# Generated by FakeRAM 2.0
VERSION 5.7 ;
BUSBITCHARS "[]" ;
PROPERTYDEFINITIONS
  MACRO width INTEGER ;
  MACRO depth INTEGER ;
  MACRO banks INTEGER ;
END PROPERTYDEFINITIONS
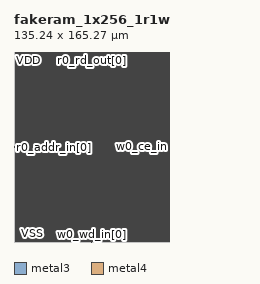
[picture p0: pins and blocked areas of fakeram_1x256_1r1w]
MACRO fakeram_1x256_1r1w
  PROPERTY width 1 ;
  PROPERTY depth 256 ;
  PROPERTY banks 1 ;
  FOREIGN fakeram_1x256_1r1w 0 0 ;
  SYMMETRY X Y R90 ;
  SIZE 135.240 BY 165.270 ;
  CLASS BLOCK ;
  PIN r0_addr_in[0]
    DIRECTION INPUT ;
    USE SIGNAL ;
    SHAPE ABUTMENT ;
    PORT
      LAYER metal3 ;
      RECT 0.000 81.900 0.070 81.970 ;
    END
  END r0_addr_in[0]
  PIN r0_addr_in[1]
    DIRECTION INPUT ;
    USE SIGNAL ;
    SHAPE ABUTMENT ;
    PORT
      LAYER metal3 ;
      RECT 0.000 82.040 0.070 82.110 ;
    END
  END r0_addr_in[1]
  PIN r0_addr_in[2]
    DIRECTION INPUT ;
    USE SIGNAL ;
    SHAPE ABUTMENT ;
    PORT
      LAYER metal3 ;
      RECT 0.000 82.180 0.070 82.250 ;
    END
  END r0_addr_in[2]
  PIN r0_addr_in[3]
    DIRECTION INPUT ;
    USE SIGNAL ;
    SHAPE ABUTMENT ;
    PORT
      LAYER metal3 ;
      RECT 0.000 82.320 0.070 82.390 ;
    END
  END r0_addr_in[3]
  PIN r0_addr_in[4]
    DIRECTION INPUT ;
    USE SIGNAL ;
    SHAPE ABUTMENT ;
    PORT
      LAYER metal3 ;
      RECT 0.000 82.460 0.070 82.530 ;
    END
  END r0_addr_in[4]
  PIN r0_addr_in[5]
    DIRECTION INPUT ;
    USE SIGNAL ;
    SHAPE ABUTMENT ;
    PORT
      LAYER metal3 ;
      RECT 0.000 82.600 0.070 82.670 ;
    END
  END r0_addr_in[5]
  PIN r0_addr_in[6]
    DIRECTION INPUT ;
    USE SIGNAL ;
    SHAPE ABUTMENT ;
    PORT
      LAYER metal3 ;
      RECT 0.000 82.740 0.070 82.810 ;
    END
  END r0_addr_in[6]
  PIN r0_addr_in[7]
    DIRECTION INPUT ;
    USE SIGNAL ;
    SHAPE ABUTMENT ;
    PORT
      LAYER metal3 ;
      RECT 0.000 82.880 0.070 82.950 ;
    END
  END r0_addr_in[7]
  PIN r0_ce_in
    DIRECTION INPUT ;
    USE SIGNAL ;
    SHAPE ABUTMENT ;
    PORT
      LAYER metal3 ;
      RECT 0.000 83.160 0.070 83.230 ;
    END
  END r0_ce_in
  PIN r0_clk
    DIRECTION INPUT ;
    USE SIGNAL ;
    SHAPE ABUTMENT ;
    PORT
      LAYER metal3 ;
      RECT 0.000 83.300 0.070 83.370 ;
    END
  END r0_clk
  PIN r0_rd_out[0]
    DIRECTION OUTPUT ;
    USE SIGNAL ;
    SHAPE ABUTMENT ;
    PORT
      LAYER metal3 ;
      RECT 67.585 165.200 67.655 165.270 ;
    END
  END r0_rd_out[0]
  PIN w0_addr_in[0]
    DIRECTION INPUT ;
    USE SIGNAL ;
    SHAPE ABUTMENT ;
    PORT
      LAYER metal3 ;
      RECT 135.170 81.900 135.240 81.970 ;
    END
  END w0_addr_in[0]
  PIN w0_addr_in[1]
    DIRECTION INPUT ;
    USE SIGNAL ;
    SHAPE ABUTMENT ;
    PORT
      LAYER metal3 ;
      RECT 135.170 82.040 135.240 82.110 ;
    END
  END w0_addr_in[1]
  PIN w0_addr_in[2]
    DIRECTION INPUT ;
    USE SIGNAL ;
    SHAPE ABUTMENT ;
    PORT
      LAYER metal3 ;
      RECT 135.170 82.180 135.240 82.250 ;
    END
  END w0_addr_in[2]
  PIN w0_addr_in[3]
    DIRECTION INPUT ;
    USE SIGNAL ;
    SHAPE ABUTMENT ;
    PORT
      LAYER metal3 ;
      RECT 135.170 82.320 135.240 82.390 ;
    END
  END w0_addr_in[3]
  PIN w0_addr_in[4]
    DIRECTION INPUT ;
    USE SIGNAL ;
    SHAPE ABUTMENT ;
    PORT
      LAYER metal3 ;
      RECT 135.170 82.460 135.240 82.530 ;
    END
  END w0_addr_in[4]
  PIN w0_addr_in[5]
    DIRECTION INPUT ;
    USE SIGNAL ;
    SHAPE ABUTMENT ;
    PORT
      LAYER metal3 ;
      RECT 135.170 82.600 135.240 82.670 ;
    END
  END w0_addr_in[5]
  PIN w0_addr_in[6]
    DIRECTION INPUT ;
    USE SIGNAL ;
    SHAPE ABUTMENT ;
    PORT
      LAYER metal3 ;
      RECT 135.170 82.740 135.240 82.810 ;
    END
  END w0_addr_in[6]
  PIN w0_addr_in[7]
    DIRECTION INPUT ;
    USE SIGNAL ;
    SHAPE ABUTMENT ;
    PORT
      LAYER metal3 ;
      RECT 135.170 82.880 135.240 82.950 ;
    END
  END w0_addr_in[7]
  PIN w0_we_in
    DIRECTION INPUT ;
    USE SIGNAL ;
    SHAPE ABUTMENT ;
    PORT
      LAYER metal3 ;
      RECT 135.170 83.160 135.240 83.230 ;
    END
  END w0_we_in
  PIN w0_ce_in
    DIRECTION INPUT ;
    USE SIGNAL ;
    SHAPE ABUTMENT ;
    PORT
      LAYER metal3 ;
      RECT 135.170 83.300 135.240 83.370 ;
    END
  END w0_ce_in
  PIN w0_clk
    DIRECTION INPUT ;
    USE SIGNAL ;
    SHAPE ABUTMENT ;
    PORT
      LAYER metal3 ;
      RECT 135.170 83.440 135.240 83.510 ;
    END
  END w0_clk
  PIN w0_wd_in[0]
    DIRECTION INPUT ;
    USE SIGNAL ;
    SHAPE ABUTMENT ;
    PORT
      LAYER metal3 ;
      RECT 67.585 0.000 67.655 0.070 ;
    END
  END w0_wd_in[0]
  PIN VSS
    DIRECTION INOUT ;
    USE GROUND ;
    PORT
      LAYER metal4 ;
      RECT 2.450 0.140 2.730 165.130 ;
      RECT 4.690 0.140 4.970 165.130 ;
      RECT 6.930 0.140 7.210 165.130 ;
      RECT 9.170 0.140 9.450 165.130 ;
      RECT 11.410 0.140 11.690 165.130 ;
      RECT 13.650 0.140 13.930 165.130 ;
      RECT 15.890 0.140 16.170 165.130 ;
      RECT 18.130 0.140 18.410 165.130 ;
      RECT 20.370 0.140 20.650 165.130 ;
      RECT 22.610 0.140 22.890 165.130 ;
      RECT 24.850 0.140 25.130 165.130 ;
      RECT 27.090 0.140 27.370 165.130 ;
      RECT 29.330 0.140 29.610 165.130 ;
      RECT 31.570 0.140 31.850 165.130 ;
      RECT 33.810 0.140 34.090 165.130 ;
      RECT 36.050 0.140 36.330 165.130 ;
      RECT 38.290 0.140 38.570 165.130 ;
      RECT 40.530 0.140 40.810 165.130 ;
      RECT 42.770 0.140 43.050 165.130 ;
      RECT 45.010 0.140 45.290 165.130 ;
      RECT 47.250 0.140 47.530 165.130 ;
      RECT 49.490 0.140 49.770 165.130 ;
      RECT 51.730 0.140 52.010 165.130 ;
      RECT 53.970 0.140 54.250 165.130 ;
      RECT 56.210 0.140 56.490 165.130 ;
      RECT 58.450 0.140 58.730 165.130 ;
      RECT 60.690 0.140 60.970 165.130 ;
      RECT 62.930 0.140 63.210 165.130 ;
      RECT 65.170 0.140 65.450 165.130 ;
      RECT 67.410 0.140 67.690 165.130 ;
      RECT 69.650 0.140 69.930 165.130 ;
      RECT 71.890 0.140 72.170 165.130 ;
      RECT 74.130 0.140 74.410 165.130 ;
      RECT 76.370 0.140 76.650 165.130 ;
      RECT 78.610 0.140 78.890 165.130 ;
      RECT 80.850 0.140 81.130 165.130 ;
      RECT 83.090 0.140 83.370 165.130 ;
      RECT 85.330 0.140 85.610 165.130 ;
      RECT 87.570 0.140 87.850 165.130 ;
      RECT 89.810 0.140 90.090 165.130 ;
      RECT 92.050 0.140 92.330 165.130 ;
      RECT 94.290 0.140 94.570 165.130 ;
      RECT 96.530 0.140 96.810 165.130 ;
      RECT 98.770 0.140 99.050 165.130 ;
      RECT 101.010 0.140 101.290 165.130 ;
      RECT 103.250 0.140 103.530 165.130 ;
      RECT 105.490 0.140 105.770 165.130 ;
      RECT 107.730 0.140 108.010 165.130 ;
      RECT 109.970 0.140 110.250 165.130 ;
      RECT 112.210 0.140 112.490 165.130 ;
      RECT 114.450 0.140 114.730 165.130 ;
      RECT 116.690 0.140 116.970 165.130 ;
      RECT 118.930 0.140 119.210 165.130 ;
      RECT 121.170 0.140 121.450 165.130 ;
      RECT 123.410 0.140 123.690 165.130 ;
      RECT 125.650 0.140 125.930 165.130 ;
      RECT 127.890 0.140 128.170 165.130 ;
      RECT 130.130 0.140 130.410 165.130 ;
      RECT 132.370 0.140 132.650 165.130 ;
      RECT 134.610 0.140 134.890 165.130 ;
    END
  END VSS
  PIN VDD
    DIRECTION INOUT ;
    USE POWER ;
    PORT
      LAYER metal4 ;
      RECT 1.330 0.140 1.610 165.130 ;
      RECT 3.570 0.140 3.850 165.130 ;
      RECT 5.810 0.140 6.090 165.130 ;
      RECT 8.050 0.140 8.330 165.130 ;
      RECT 10.290 0.140 10.570 165.130 ;
      RECT 12.530 0.140 12.810 165.130 ;
      RECT 14.770 0.140 15.050 165.130 ;
      RECT 17.010 0.140 17.290 165.130 ;
      RECT 19.250 0.140 19.530 165.130 ;
      RECT 21.490 0.140 21.770 165.130 ;
      RECT 23.730 0.140 24.010 165.130 ;
      RECT 25.970 0.140 26.250 165.130 ;
      RECT 28.210 0.140 28.490 165.130 ;
      RECT 30.450 0.140 30.730 165.130 ;
      RECT 32.690 0.140 32.970 165.130 ;
      RECT 34.930 0.140 35.210 165.130 ;
      RECT 37.170 0.140 37.450 165.130 ;
      RECT 39.410 0.140 39.690 165.130 ;
      RECT 41.650 0.140 41.930 165.130 ;
      RECT 43.890 0.140 44.170 165.130 ;
      RECT 46.130 0.140 46.410 165.130 ;
      RECT 48.370 0.140 48.650 165.130 ;
      RECT 50.610 0.140 50.890 165.130 ;
      RECT 52.850 0.140 53.130 165.130 ;
      RECT 55.090 0.140 55.370 165.130 ;
      RECT 57.330 0.140 57.610 165.130 ;
      RECT 59.570 0.140 59.850 165.130 ;
      RECT 61.810 0.140 62.090 165.130 ;
      RECT 64.050 0.140 64.330 165.130 ;
      RECT 66.290 0.140 66.570 165.130 ;
      RECT 68.530 0.140 68.810 165.130 ;
      RECT 70.770 0.140 71.050 165.130 ;
      RECT 73.010 0.140 73.290 165.130 ;
      RECT 75.250 0.140 75.530 165.130 ;
      RECT 77.490 0.140 77.770 165.130 ;
      RECT 79.730 0.140 80.010 165.130 ;
      RECT 81.970 0.140 82.250 165.130 ;
      RECT 84.210 0.140 84.490 165.130 ;
      RECT 86.450 0.140 86.730 165.130 ;
      RECT 88.690 0.140 88.970 165.130 ;
      RECT 90.930 0.140 91.210 165.130 ;
      RECT 93.170 0.140 93.450 165.130 ;
      RECT 95.410 0.140 95.690 165.130 ;
      RECT 97.650 0.140 97.930 165.130 ;
      RECT 99.890 0.140 100.170 165.130 ;
      RECT 102.130 0.140 102.410 165.130 ;
      RECT 104.370 0.140 104.650 165.130 ;
      RECT 106.610 0.140 106.890 165.130 ;
      RECT 108.850 0.140 109.130 165.130 ;
      RECT 111.090 0.140 111.370 165.130 ;
      RECT 113.330 0.140 113.610 165.130 ;
      RECT 115.570 0.140 115.850 165.130 ;
      RECT 117.810 0.140 118.090 165.130 ;
      RECT 120.050 0.140 120.330 165.130 ;
      RECT 122.290 0.140 122.570 165.130 ;
      RECT 124.530 0.140 124.810 165.130 ;
      RECT 126.770 0.140 127.050 165.130 ;
      RECT 129.010 0.140 129.290 165.130 ;
      RECT 131.250 0.140 131.530 165.130 ;
      RECT 133.490 0.140 133.770 165.130 ;
    END
  END VDD
  OBS
    LAYER metal1 ;
    RECT 0 0 135.240 165.270 ;
    LAYER metal2 ;
    RECT 0 0 135.240 165.270 ;
    LAYER metal3 ;
    RECT 0 0 135.240 165.270 ;
    LAYER metal4 ;
    RECT 0 0 135.240 165.270 ;
    LAYER OVERLAP ;
    RECT 0 0 135.240 165.270 ;
  END
END fakeram_1x256_1r1w

END LIBRARY
